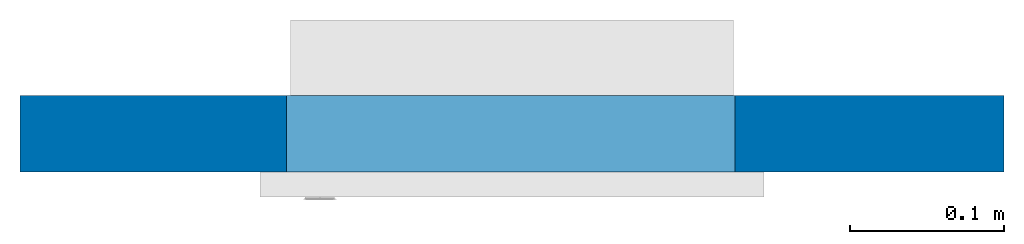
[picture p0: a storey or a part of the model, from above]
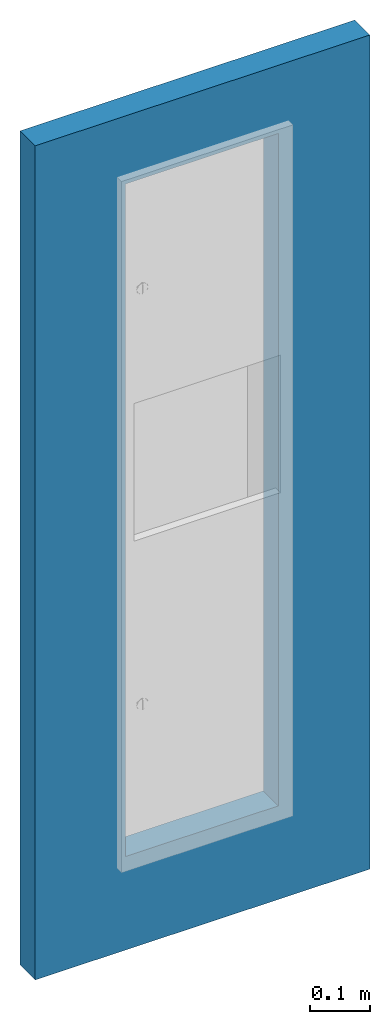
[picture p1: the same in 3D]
Properties of the parts of a building model (IFC2X3)

# File
Description: ViewDefinition [CoordinationView]
Time: 2018-07-06T13:00:55
Written by: The EXPRESS Data Manager Version 5.01.0100.02.64mod : 6 Jun 2012
Made in: 20140709_2115(x64) - Exporter 2014.0.2014.0709 - Default UI
Comment: STEP Physical File produced by: The EXPRESS Data Manager Version 5.01.0100.02.64mod : 6 Jun 2012 * Module: EDMstepFileFactory/EDMstandAlone * Creation date: Fri Jul 06 13:00:55 2018 * Host: BIM-HP * Database: C:\Users\dcole\AppData\Local\Temp\{2FC432C0-EF82-404F-8B69-A76A561ACE7D}\ifc * Database version: 5507 * Database creation date: Fri Jul 06 13:00:54 2018 * Schema: IFC2X3 * Model: DataRepository.ifc * Model creation date: Fri Jul 06 13:00:55 2018 * Header model: DataRepository.ifc_HeaderModel * Header model creation date: Fri Jul 06 13:00:55 2018 * EDMuser: sdai-user * EDMgroup: sdai-group * License ID and type: 5605 : Permanent license. Expiry date: * EDMstepFileFactory options: 020000

# IfcProject
LongName: P:\Fastrack\53721_DOLPHIN SOLUTIONS LIMITED\ADDITIONAL DRAWINGS 2018 BIM\IFC\BC709.ifc

# IfcSite, Default
RefLatitude: 42, 24, 53, 508911; RefLongitude: -71, -15, -29, -58837; RefElevation: 0 mm

# IfcBuilding
Pset_BuildingCommon - NumberOfStoreys: 1

# IfcBuildingStorey, Level 1
LongName: Level 1; Elevation: 0 mm
Constraints - Elevation Base: Project Base Point; Elevation: 0 mm
Identity Data - Structural: no; Name: Level 1; Building Story: yes
Dimensions - Computation Height: 0 mm
Graphics - Color: 0; Symbol at End 1 Default: no; Line Weight: 1; Line Pattern: -3000010; Symbol at End 2 Default: yes

# IfcBuildingElementProxy: BC709 Dolphin Recessed Paper Towel Dispenser and Bin Combination Unit, BC709:BC709 Dolphin Recessed Paper Towel Dispenser and Bin Combination Unit:79023
In: Level 1
Constraints - Level: Level: Level 1; Offset: 0 mm; Moves With Nearby Elements: no; Host: Level : Level 1
Dimensions - Volume: 0.00829295 m3; Recess: 1247 x 288 x 99mm; Height: 1397mm; Capacity Paper Towels: 600 paper towels; Width: 328mm; Projection: 16mm
Phasing - Phase Created: New Construction
Pset_ManufacturerTypeInformation - Manufacturer: Dolphin Solutions Limited
Pset_BuildingElementProxyCommon - Reference: BC709 Dolphin Recessed Paper Towel Dispenser and Bin Combination Unit
Identity Data - Tel No.: +44 (0) 1424 202224; Description: Recessed paper towel dispenser and bin combination unit; Fax No.: +44 (0) 1424 205200; Address: Southpoint, Compass Park, Bodiam, Robertsbridge, TN32 5BS; Model: BC709; Email: info@dolphinsolutions.co.uk; Assembly Description: Other Plumbing Fixtures; Manufacturer: Dolphin Solutions Limited; Assembly Code: D2010900; URL: www.dolphinsolutions.co.uk
General - Capacity Bin: 19 litres; Product Data: Combination unit constructed from high quality satin stainless steel. Lockable. Removable stainless steel waste receptacle. Holds 600 paper towels. Waste capacity 19 litres.; Product Page Link: www.dolphinsolutions.co.uk/product/dolphin-recessed-paper-towel-dispenser-bin-combination-unit/

# IfcOpeningElement: Opening
In: Level 1
Structural - Structural Usage: Non-bearing; Structural: no; Enable Analytical Model: no
Constraints - Base Constraint: Level: Level 1; Base Extension Distance: 0 mm; Base is Attached: no; Top Offset: 0 mm; Room Bounding: yes; Top is Attached: no; Unconnected Height: 1685.82 mm; Location Line: Finish Face: Interior; Related to Mass: no; Top Extension Distance: 0 mm; Base Offset: -171.611 mm
Phasing - Phase Created: New Construction
Dimensions - Length: 640 mm; Area: 0.682263 m2; Volume: 0.0341131 m3
Analytical Properties - Roughness: 1; Absorptance: 0.1
Graphics - Coarse Scale Fill Color: 8454143
Construction - Wrapping at Inserts: Do not wrap; Function: Exterior; Width: 50 mm

# IfcWallStandardCase: Basic Wall:Wall 1, Basic Wall:Wall 1:3092
In: Level 1
Type - PredefinedType: STANDARD; Material: Default Wall 50 mm
Type - Analytical Properties - Roughness: 1; Absorptance: 0.1
Type - Graphics - Coarse Scale Fill Color: 8454143
Type - Construction - Wrapping at Inserts: Do not wrap; Function: Exterior; Width: 50 mm
Structural - Structural Usage: Non-bearing; Structural: no; Enable Analytical Model: no
Constraints - Base Constraint: Level: Level 1; Base Extension Distance: 0 mm; Base is Attached: no; Top Offset: 0 mm; Room Bounding: yes; Top is Attached: no; Unconnected Height: 1685.82 mm; Location Line: Finish Face: Interior; Related to Mass: no; Top Extension Distance: 0 mm; Base Offset: -171.611 mm
Phasing - Phase Created: New Construction
Dimensions - Length: 640 mm; Area: 0.682263 m2; Volume: 0.0341131 m3
Pset_WallCommon - Reference: Wall 1; LoadBearing: no; ExtendToStructure: no; IsExternal: yes
